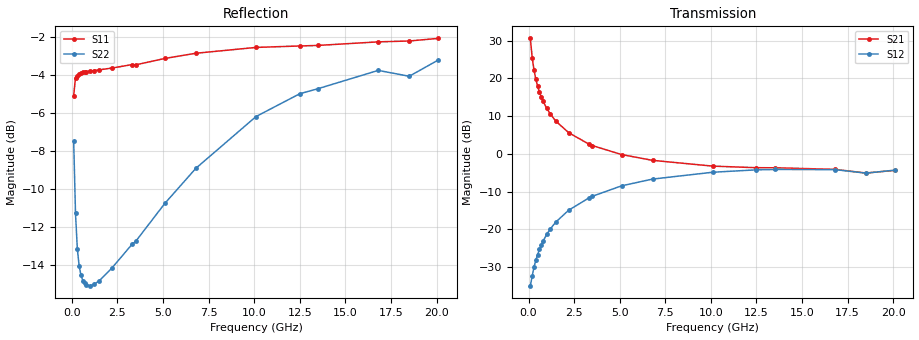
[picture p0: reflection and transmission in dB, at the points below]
!  Infineon Technologies AG
! BFR380L3 , PF131585-7, No.6, Th 09.10.01, soldered on pcb-board, measured with PP GSG850
!  Vce=1.5 V,  Ic=80.0 mA
! Common Emitter S-Parameters:  15. November 2001
#  GHz  S  MA  R  50
! f  S11  S21  S12  S22
! GHz  Mag  Ang  Mag  Ang  Mag  Ang  Mag  Ang
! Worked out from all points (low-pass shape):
!   201 points, 100 MHz to 20.1 GHz, reference 50 ohm
!   highest |S21| = 30.59 dB at 100 MHz (marker M1); lowest = -5.1 dB at 18.5 GHz (marker M2)
!   |S21| within 3 dB of the highest: start of sweep to 159 MHz
!   lowest |S11| = -5.1 dB at 100 MHz (marker M3), VSWR 3.52, Z = 16.2 - j17.8 ohm
!   |S11| at or under -10 dB: nowhere
!   |S22| runs from -15.1 to -3.2 dB; largest |S21 - S12| = 34
!   S11 on the Smith chart (normalised r, x): 100 MHz: 0.32, -0.36; 700 MHz: 0.22, +0.03; 3.3 GHz: 0.23, +0.39; 6.8 GHz: 0.28, +0.84; 12.5 GHz: 0.52, +1.58; 20.1 GHz: 1.04, +2.62
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0.1  0.5574 -137.2  33.83 119.7  0.01796 54.7  0.4225 -77.2
0.2  0.6208 -158.8  18.84 103.5  0.02401 57.5  0.2723 -107.0
0.3  0.6297 -168.1  12.89 96.7  0.0316 62.4  0.2198 -123.4
0.4  0.6364 -173.5  9.767 92.2  0.0388 65.2  0.1976 -134.5
0.5  0.6392 -177.3  7.853 88.8  0.04647 67.7  0.1869 -142.1
0.6  0.6418 179.5  6.569 86.2  0.0543 69.2  0.1809 -147.7
0.7  0.6423 176.9  5.655 83.7  0.06195 69.9  0.1779 -152.1
0.8  0.6448 174.6  4.961 81.4  0.06998 70.5  0.1761 -155.5
1  0.6468 170.5  3.995 77.4  0.08596 70.7  0.1754 -160.6
1.2  0.6491 166.7  3.352 73.7  0.1016 70.2  0.1768 -164.3
1.5  0.652 161.7  2.71 68.4  0.1253 69.1  0.1806 -168.5
2.2  0.6592 150.8  1.908 57.3  0.1793 64.9  0.1954 -175.7
3.3  0.6732 135.5  1.351 42.2  0.2598 57.0  0.2256 174.6
3.5  0.6722 132.8  1.288 39.7  0.2743 55.4  0.2297 173.5
5.1  0.6989 114.0  0.9792 22.7  0.3771 42.8  0.2894 159.0
6.8  0.7213 97.0  0.8203 9.5  0.4634 30.2  0.3582 142.6
10.1  0.7474 73.0  0.688 -7.7  0.5709 7.9  0.4909 115.9
12.5  0.754 60.8  0.6555 -17.5  0.6143 -6.6  0.5639 97.6
13.5  0.7565 56.8  0.654 -21.5  0.6214 -12.3  0.5815 91.3
16.8  0.7731 45.5  0.6239 -32.5  0.6184 -27.4  0.6499 72.3
18.5  0.7772 43.9  0.5572 -39.9  0.5555 -35.5  0.6271 67.8
20.1  0.7897 37.0  0.605 -43.5  0.6091 -40.4  0.6926 57.5
